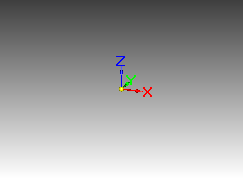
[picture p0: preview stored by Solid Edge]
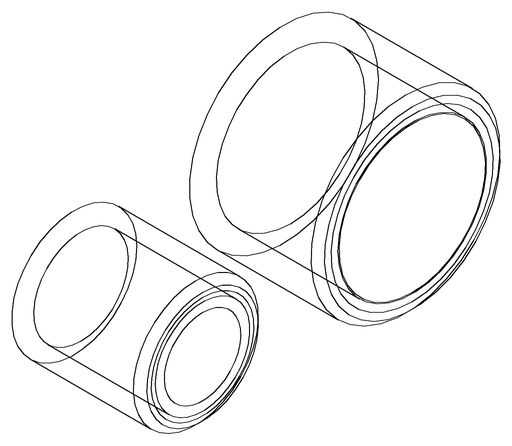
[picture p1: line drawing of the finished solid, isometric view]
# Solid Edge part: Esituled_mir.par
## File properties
Author: Türk
Template: Iso Part.par
Last saved by: Türk
Revision: 2
Application: Solid Edge
Accuracy: 0,990
Username: Türk
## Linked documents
Esituled.par
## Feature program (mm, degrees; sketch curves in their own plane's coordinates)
part copy "CopiedPart_1"
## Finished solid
Body 1: solid body, 18 faces, 14 edges, 4 vertices, 2 separate solids, 2 internal voids.
  Faces by surface: plane 8, cylinder 4, spun 4, torus 2
  Edges by curve: circle 14
Bounding box of the edges (mm; curved faces can reach further): 271.498 x 95.000 x 140.000, from (-579.1669, 645, 95.798) to (-307.6693, 740, 235.798).
Cylindrical faces by radius (mm): R35 x1, R46.25 x1, R55 x1, R70 x1
Toroidal faces (ring radius, tube radius in mm): R41.25 r5 x1, R65 r5 x1
Planar faces by outward normal: +y 4, -y 4
